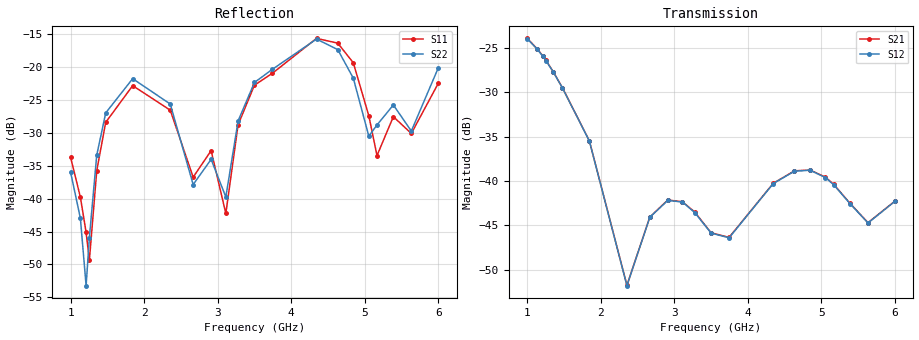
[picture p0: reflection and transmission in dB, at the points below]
!Agilent Technologies,E8364B,MY43040528,A.07.50.67
!Agilent E8364B: A.07.50.67
!Date: Sunday, March 01, 2026 22:34:19
!Correction: S11(Full 2 Port(1,2))
!S21(Full 2 Port(1,2))
!S12(Full 2 Port(1,2))
!S22(Full 2 Port(1,2))
!S2P File: Measurements: S11, S21, S12, S22:
# Hz S  dB  R 50
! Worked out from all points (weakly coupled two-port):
!   451 points, 1 GHz to 6 GHz, reference 50 ohm
!   highest |S21| = -23.90 dB at 1 GHz (marker M1); lowest = -51.8 dB at 2.356 GHz (marker M2)
!   lowest |S11| = -49.4 dB at 1.256 GHz (marker M3), VSWR 1.01, Z = 50 - j0.335 ohm
!   |S11| at or under -10 dB: start of sweep to end of sweep
!   |S22| runs from -53.2 to -15.7 dB; largest |S21 - S12| = 0.00023
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1e9  -33.71 14.3  -23.90 155.1  -23.94 155.2  -35.97 -28.7
1.133333e9  -39.78 5.4  -25.07 79.1  -25.10 79.1  -42.98 -17.6
1.211111e9  -45.12 -12.7  -25.88 35.0  -25.91 35.0  -53.24 57.1
1.255556e9  -49.40 -81.4  -26.39 9.9  -26.43 9.9  -45.95 123.9
1.355556e9  -35.77 -165.2  -27.69 -46.1  -27.72 -46.0  -33.41 112.3
1.477778e9  -28.40 155.2  -29.46 -112.9  -29.49 -112.8  -26.96 81.6
1.844444e9  -22.82 74.8  -35.45 52.0  -35.48 52.1  -21.76 -11.3
2.355556e9  -26.55 0.2  -51.76 -148.3  -51.81 -148.1  -25.62 -114.9
2.666667e9  -36.74 15.6  -44.06 104.6  -44.09 104.7  -37.86 -124.0
2.911111e9  -32.70 18.5  -42.14 -21.6  -42.19 -21.6  -34.03 -118.8
3.111111e9  -42.26 56.1  -42.34 -126.4  -42.37 -126.3  -39.75 -83.5
3.277778e9  -28.77 90.7  -43.50 149.1  -43.56 149.2  -28.19 -74.5
3.5e9  -22.75 54.9  -45.84 47.4  -45.87 47.4  -22.34 -121.1
3.744444e9  -20.94 26.7  -46.36 -47.5  -46.41 -47.4  -20.33 -160.7
4.344444e9  -15.63 -47.3  -40.26 25.0  -40.29 25.1  -15.74 100.3
4.633333e9  -16.36 -95.2  -38.85 -133.6  -38.89 -133.7  -17.34 42.1
4.844444e9  -19.34 -132.8  -38.75 105.4  -38.78 105.4  -21.68 2.0
5.055556e9  -27.41 -158.0  -39.57 -19.0  -39.61 -19.0  -30.51 3.6
5.166667e9  -33.46 -123.8  -40.37 -85.9  -40.41 -85.9  -28.80 29.3
5.388889e9  -27.54 -99.5  -42.51 134.3  -42.55 134.3  -25.76 4.1
5.633333e9  -30.09 -102.4  -44.70 -36.8  -44.73 -36.8  -29.72 4.6
6e9  -22.47 -82.5  -42.26 61.5  -42.29 61.4  -20.12 -19.3
